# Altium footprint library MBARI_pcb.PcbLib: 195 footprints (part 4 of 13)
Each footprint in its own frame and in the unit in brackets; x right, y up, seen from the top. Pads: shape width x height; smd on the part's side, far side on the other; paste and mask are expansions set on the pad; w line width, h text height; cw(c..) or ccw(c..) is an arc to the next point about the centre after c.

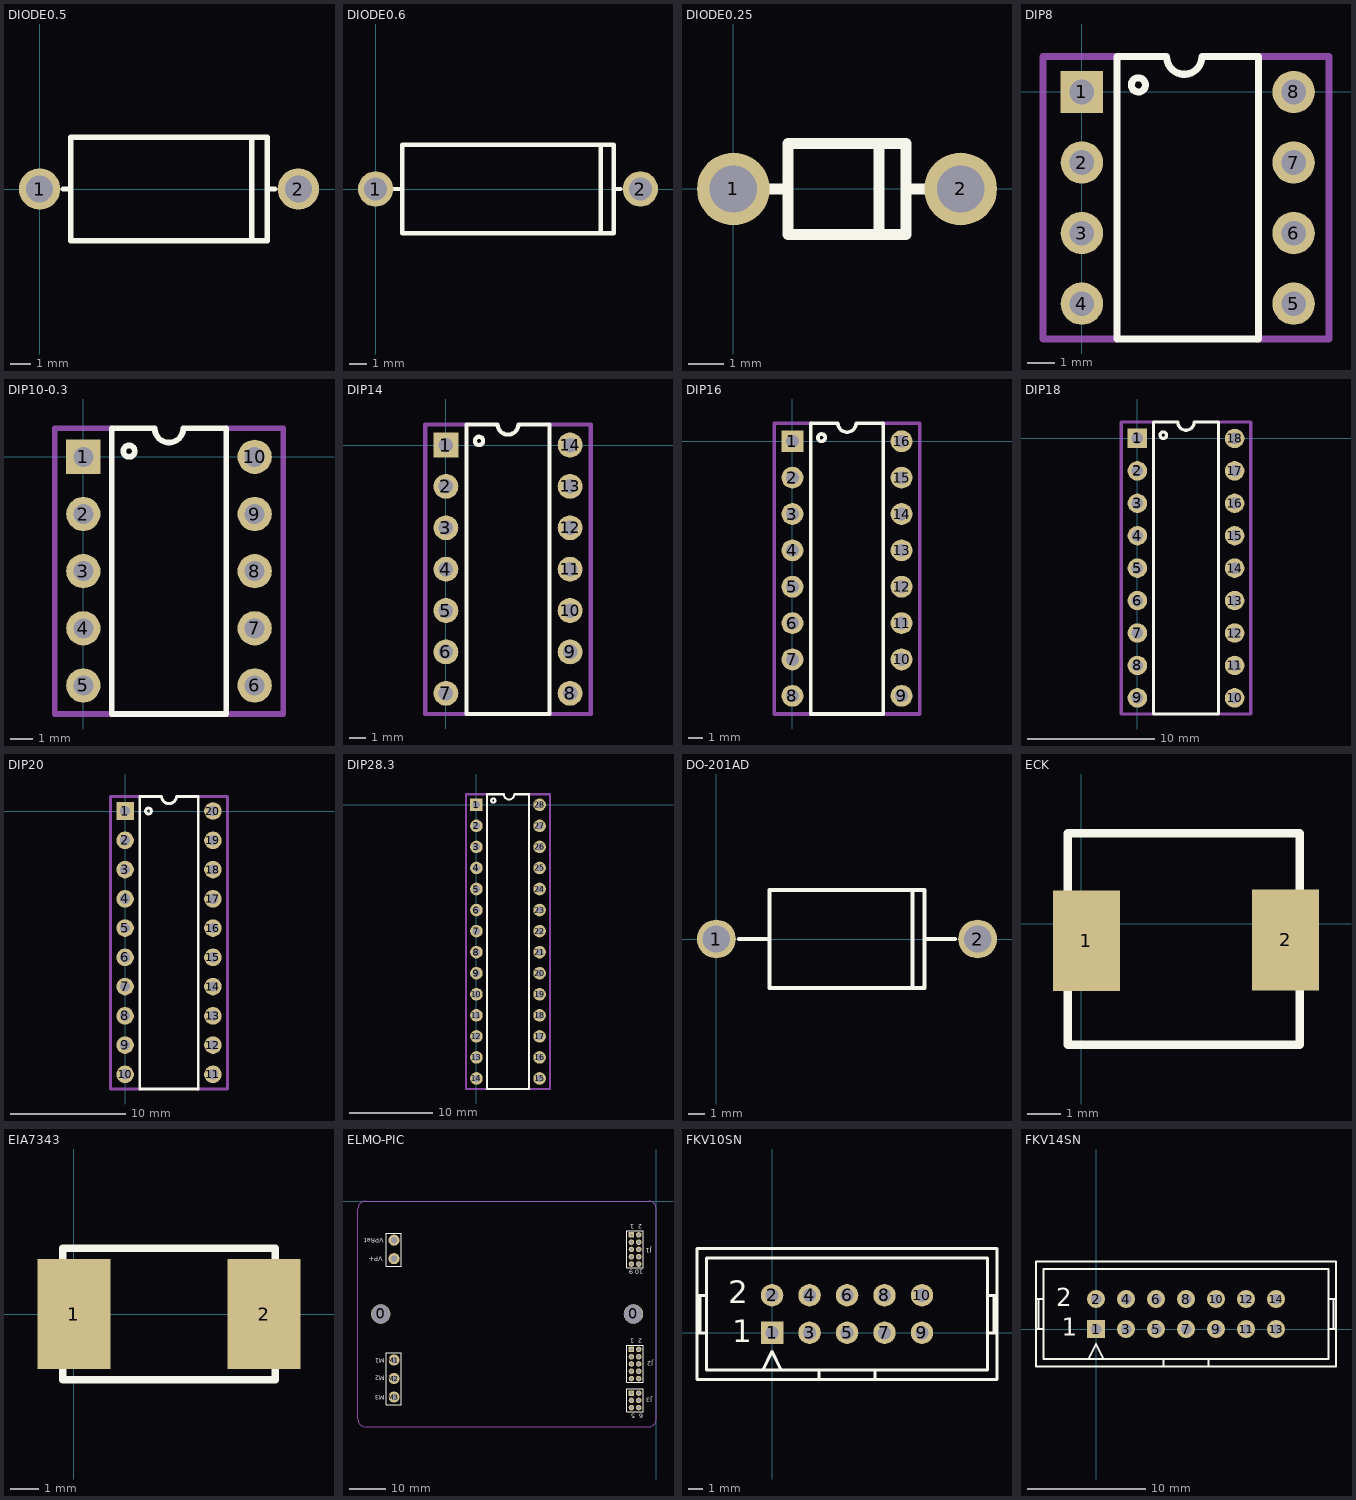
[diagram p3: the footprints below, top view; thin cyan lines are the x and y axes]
## DIODE0.5 [mil]
pads (2):
  round 80 hole 52: 1(0,0) 2(500,0)
TopOverlay:
  lines w10: 45,0 60,0 ; 410,-100 410,100 ; 440,0 455,0 ; 60,0 60,-100 440,-100 440,100 60,100 60,0

## DIODE0.6 [mil]
pads (2):
  round 80 hole 52: 1(0,0) 2(600,0)
TopOverlay:
  lines w10: 40,0 55,0 ; 510,-100 510,100 ; 540,0 555,0 ; 60,-100 540,-100 540,100 60,100 60,0 60,-100

## DIODE0.25 [mil]
pads (2):
  round 80 hole 52: 1(0,0) 2(250,0)
TopOverlay:
  lines w12: 40,0 60,0 ; 160,-50 160,50 ; 190,0 210,0 ; 60,-50 190,-50 190,50 60,50 60,-50

## DIP8 [mil]
pads (8):
  rect 60x60 hole 35: 1(0,0)
  round 60 hole 35: 2(0,-100) 3(0,-200) 4(0,-300) 5(300,-300) 6(300,-200) 7(300,-100) 8(300,0)
TopOverlay:
  circle w10: c80,10 r10
  lines w10: 50,-350 50,50 120,50 ccw(c145,50) 170,50 250,50 250,-350 50,-350
Mechanical1:
  lines w10: 50,-350 -55,-350 -55,50 50,50 ; 249,-350 350,-350 350,50 249,50

## DIP10-0.3 [mil] "10 pin DIP 0.3\" spacing"
pads (10):
  rect 60x60 hole 35: 1(0,0)
  round 60 hole 35: 2(0,-100) 3(0,-200) 4(0,-300) 5(0,-400) 6(300,-400) 7(300,-300) 8(300,-200) 9(300,-100) 10(300,0)
TopOverlay:
  circle w10: c80,10 r10
  lines w10: 50,-450 50,50 125,50 ccw(c150,50) 175,50 250,50 250,-450 50,-450
Mechanical1:
  lines w10: 50,-450 -50,-450 -50,50 50,50 ; 250,-450 350,-450 350,50 250,50

## DIP14 [mil]
pads (14):
  rect 60x60 hole 35: 1(0,0)
  round 60 hole 35: 2(0,-100) 3(0,-200) 4(0,-300) 5(0,-400) 6(0,-500) 7(0,-600) 8(300,-600) 9(300,-500) 10(300,-400) 11(300,-300) 12(300,-200) 13(300,-100) 14(300,0)
TopOverlay:
  circle w10: c80,10 r10
  lines w10: 50,-650 250,-650 250,50 175,50 cw(c150,50) 125,50 50,50 50,-650
Mechanical1:
  lines w10: 50,-650 -50,-650 -50,50 50,50 ; 250,-650 350,-650 350,50 250,50

## DIP16 [mil]
pads (16):
  rect 60x60 hole 35: 1(0,0)
  round 60 hole 35: 2(0,-100) 3(0,-200) 4(0,-300) 5(0,-400) 6(0,-500) 7(0,-600) 8(0,-700) 9(300,-700) 10(300,-600) 11(300,-500) 12(300,-400) 13(300,-300) 14(300,-200) 15(300,-100) 16(300,0)
TopOverlay:
  circle w10: c80,10 r10
  lines w10: 50,-750 250,-750 250,50 175,50 cw(c150,50) 125,50 50,50 50,-750
Mechanical1:
  lines w10: 50,-750 -50,-750 -50,50 50,50 ; 250,-750 350,-750 350,50 250,50

## DIP18 [mil]
pads (18):
  rect 60x60 hole 35: 1(0,0)
  round 60 hole 35: 2(0,-100) 3(0,-200) 4(0,-300) 5(0,-400) 6(0,-500) 7(0,-600) 8(0,-700) 9(0,-800) 10(300,-800) 11(300,-700) 12(300,-600) 13(300,-500) 14(300,-400) 15(300,-300) 16(300,-200) 17(300,-100) 18(300,0)
TopOverlay:
  circle w10: c80,10 r10
  lines w10: 175,50.27 cw(c150,50.27) 125,50.27 50,50.27 50,-849.73 249.45,-849.73 ; 175,50.27 250,50.27 250,-849.17
Mechanical1:
  lines w10: 49.73,-849.73 -50,-849.73 -50,50.27 50,50.27 ; 250,50.27 350,50.27 350,-849.73 250.28,-849.73

## DIP20 [mil]
pads (20):
  rect 60x60 hole 35: 1(0,0)
  round 60 hole 35: 2(0,-100) 3(0,-200) 4(0,-300) 5(0,-400) 6(0,-500) 7(0,-600) 8(0,-700) 9(0,-800) 10(0,-900) 11(300,-900) 12(300,-800) 13(300,-700) 14(300,-600) 15(300,-500) 16(300,-400) 17(300,-300) 18(300,-200) 19(300,-100) 20(300,0)
TopOverlay:
  circle w10: c80,0 r10
  lines w10: 50,50 50,-950 250,-950 250,50 175,50.27 ; 50,50.27 125,50.27 ccw(c150,50.27) 175,50.27
Mechanical1:
  lines w10: 50,-950 -50,-950 -50,50 50,50 ; 250,-950 350,-950 350,50 250,50

## DIP28.3 [mil]
pads (28):
  rect 60x60 hole 35: 1(0,0)
  round 60 hole 35: 2(0,-100) 3(0,-200) 4(0,-300) 5(0,-400) 6(0,-500) 7(0,-600) 8(0,-700) 9(0,-800) 10(0,-900) 11(0,-1000) 12(0,-1100) 13(0,-1200) 14(0,-1300) 15(300,-1300) 16(300,-1200) 17(300,-1100) 18(300,-1000) 19(300,-900) 20(300,-800) 21(300,-700) 22(300,-600) 23(300,-500) 24(300,-400) 25(300,-300) 26(300,-200) 27(300,-100) 28(300,0)
TopOverlay:
  circle w10: c80,20 r10
  lines w10: 50,-1350 250,-1350 250,50 180,50 cw(c155,50) 130,50 50,50 50,-1350
Mechanical1:
  lines w10: 50,-1350 -50,-1350 -50,50 50,50 ; 250,-1350 350,-1350 350,50 250,50

## DO-201AD [mil]
pads (2):
  round 95 hole 67: 1(0,0) 2(640,0)
TopOverlay:
  lines w10: 55,0 130,0 ; 480,-120 480,120 ; 510,0 585,0 ; 130,0 130,120 510,120 510,-120 130,-120 130,0

## ECK [mm]
pads (2):
  rect 2x3 smd: 1(0.15,-0.5) 2(6.075,-0.475)
TopOverlay:
  lines w0.254: -0.4,-2 -0.4,-3.6 3.1,-3.6 6.5,-3.6 6.5,-1.975 ; -0.4,1 -0.4,2.7 3.1,2.7 6.5,2.7 6.5,1

## EIA7343 [mil] "EIA 7343 size SMD"
height 120
pads (2):
  rect 100x150 smd: 1(0,0) 2(260,0)
TopOverlay:
  lines w10: -15,-75 -15,-90 275,-90 275,-75 ; -15,75 -15,90 275,90 275,75

## ELMO-PIC [mil]
pads (33):
  round 210 hole 201: 0(-2982.28,-1220.47) 0(-246.06,-1220.47)
  rect 60x60 hole 35: J1.1(-267.32,-364.17) J2.1(-267.32,-1604.33) J3.1(-267.32,-2076.77)
  round 60 hole 35: J1.2(-188.58,-364.17) J1.3(-267.32,-442.91) J1.4(-188.58,-442.91) J1.5(-267.32,-521.65) J1.6(-188.58,-521.65) J1.7(-267.32,-600.39) J1.8(-188.58,-600.39) J1.9(-267.32,-679.13) J1.10(-188.58,-679.13) J2.2(-188.58,-1604.33) J2.3(-267.32,-1683.07) J2.4(-188.58,-1683.07) J2.5(-267.32,-1761.81) J2.6(-188.58,-1761.81) J2.7(-267.32,-1840.55) J2.8(-188.58,-1840.55) J2.9(-267.32,-1919.29) J2.10(-188.58,-1919.29) J3.2(-188.58,-2076.77) J3.3(-267.32,-2155.51) J3.4(-188.58,-2155.51) J3.5(-267.32,-2234.25) J3.6(-188.58,-2234.25)
  round 120 hole 70: M1(-2838.58,-1719.29) M2(-2838.58,-1919.29) M3(-2838.58,-2119.29) VP+(-2838.58,-621.65) VPRet(-2838.58,-421.65)
TopOverlay:
  lines w10: -145.67,-2031.5 -318.9,-2031.5 -318.9,-2279.53 -141.73,-2279.53 -141.73,-2031.5 ; -145.67,-1559.06 -318.9,-1559.06 -318.9,-1960.63 -141.73,-1960.63 -141.73,-1559.06 ; -145.67,-318.9 -318.9,-318.9 -318.9,-720.47 -141.73,-720.47 -141.73,-318.9 ; -2921.26,-2200.79 -2921.26,-1641.73 -2759.84,-1641.73 -2759.84,-2200.79 -2921.26,-2200.79 ; -2921.26,-702.36 -2921.26,-344.09 -2759.84,-344.09 -2759.84,-702.36 -2921.26,-702.36
  text "M3" at -2940,-2100 h50
  text "M2" at -2940,-1890 h50
  text "M1" at -2940,-1700 h50
  text "VPRet" at -2950,-400 h50
  text "VP+" at -2960,-600 h50
  text "10 9" at -140,-740 h50
  text "6  5" at -140,-2300 h50
  text "2  1" at -150,-250 h50
  text "2  1" at -150,-1490 h50
  text "J1" at -50,-510 h50
  text "J2" at -30,-1730 h50
  text "J3" at -40,-2130 h50
Mechanical1:
  lines w10: -3228.35,-2362.2 ccw(c-3149.61,-2362.2) -3149.61,-2440.94 -78.74,-2440.94 ccw(c-78.74,-2362.2) 0,-2362.2 0,-78.74 ccw(c-78.74,-78.74) -78.74,0 -3149.61,0 ccw(c-3149.61,-78.74) -3228.35,-78.74 -3228.35,-2362.2

## FKV10SN [mil]
pads (10):
  rect 60x60 hole 35: 1(0,0)
  round 60 hole 35: 2(0,100) 3(100,0) 4(100,100) 5(200,0) 6(200,100) 7(300,0) 8(300,100) 9(400,0) 10(400,100)
TopOverlay:
  lines w8: -200,0 -175,0 ; -200,100 -175,100 ; -191.67,0 -191.67,100 ; -25,-100 0,-50 25,-100 ; 125,-125 125,-100 ; 275,-125 275,-100 ; 575,0 600,0 ; 575,100 600,100 ; 591.67,0 591.67,100 ; 125,-100 275,-100 ; 125,-100 -175,-100 -175,200 575,200 575,-100 275,-100 ; -200,-125 600,-125 600,225 -200,225 -200,-125
  text "1" at -106,-26 h60
  text "2" at -117,79 h60

## FKV14SN [mil]
pads (14):
  rect 60x60 hole 35: 1(0,0)
  round 60 hole 35: 2(0,100) 3(100,0) 4(100,100) 5(200,0) 6(200,100) 7(300,0) 8(300,100) 9(400,0) 10(400,100) 11(500,0) 12(500,100) 13(600,0) 14(600,100)
TopOverlay:
  lines w8: -200,0 -175,0 ; -200,100 -175,100 ; -191.67,0 -191.67,100 ; -25,-100 0,-50 25,-100 ; 225,-125 225,-100 ; 375,-125 375,-100 ; 775,0 800,0 ; 775,100 800,100 ; 791.67,0 791.67,100 ; 225,-100 375,-100 ; 225,-100 -175,-100 -175,200 775,200 775,-100 375,-100 ; -200,-125 800,-125 800,225 -200,225 -200,-125
  text "2" at -132,76 h60
  text "1" at -115,-23 h60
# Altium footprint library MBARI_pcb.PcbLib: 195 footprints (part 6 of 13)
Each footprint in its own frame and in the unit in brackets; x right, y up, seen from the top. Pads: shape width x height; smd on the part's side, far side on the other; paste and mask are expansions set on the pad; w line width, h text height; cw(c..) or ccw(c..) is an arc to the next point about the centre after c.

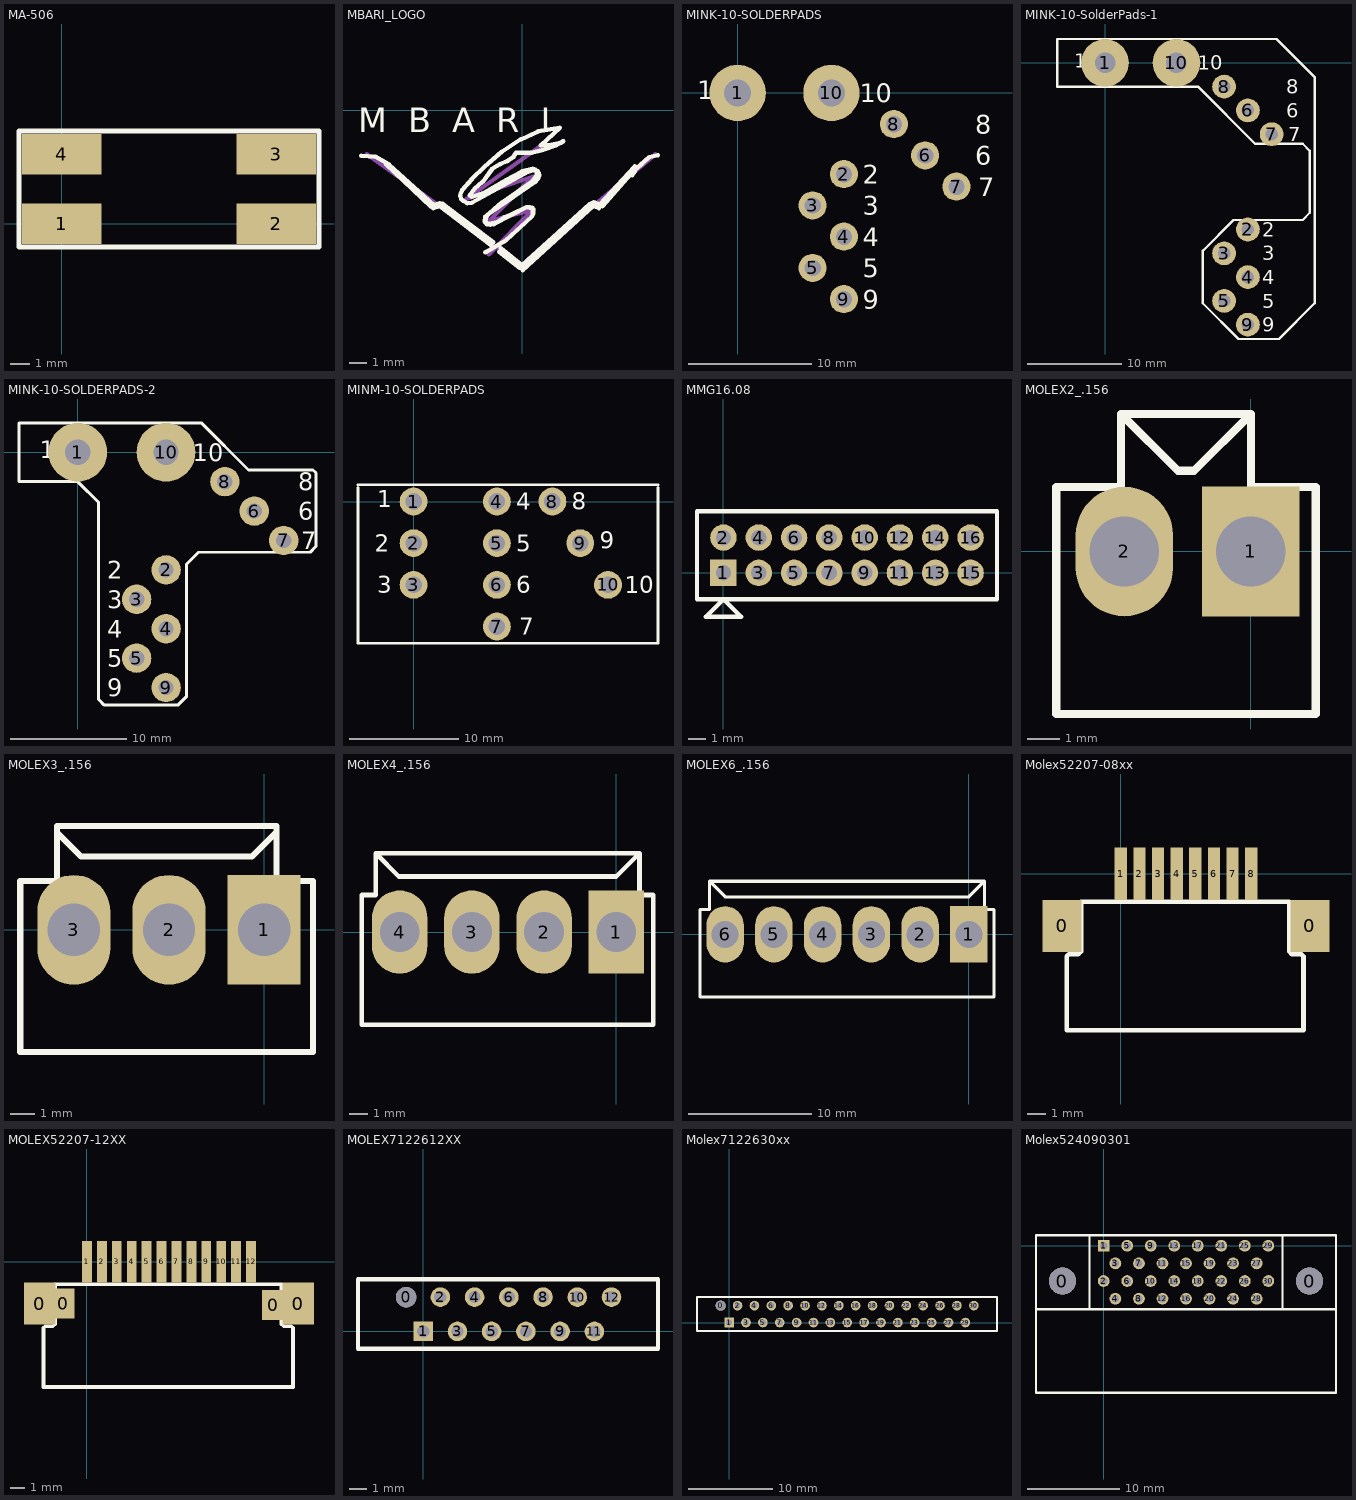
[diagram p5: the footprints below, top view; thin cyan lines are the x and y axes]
## MA-506 [mm] "Epson Quartz Crystal"
height 4.572
pads (4):
  rect 4.1x2.1 smd: 1(0,0) 2(11.1,0) 3(11.1,3.6) 4(0,3.6)
TopOverlay:
  lines w0.254: -2.2,-1.2 -2.2,4.8 13.3,4.8 13.3,-1.2 -2.2,-1.2

## MBARI_LOGO [mil]
TopOverlay:
  lines w10: -363,-103 -331,-105 -300,-123 -199,-214 -186,-210 -179,-211 -65,-298 ; -308,-121 -205,-218 ; -200,-221 -185,-217 -70,-305 ; -83,-321 -37,-294 22,-240 25,-233 25,-223 23,-220 17,-219 10,-219 ; -52,-319 -5,-356 ; -48,-312 0,-350 152,-212 161,-208 175,-213 254,-127 257,-132 286,-106 306,-102 ; 24,-234 24,-226 22,-222 17,-220 10,-219 ; 158,-216 173,-221 ; 180,-217 245,-144 ; 248,-147 254,-138 ; 10,-219 3,-222 -40,-242 -57,-253 -80,-257 -84,-252 -83,-240 -45,-208 23,-161 34,-145 30,-134 24,-132 0,-138 -36,-158 -84,-186 -114,-196 -118,-192 -107,-177 -89,-162 -67,-132 -49,-122 -34,-115 -21,-107 -14,-96 21,-96 44,-91 60,-85 76,-80 93,-70 88,-74 59,-79 42,-79 85,-40 36,-48 -3,-66 -46,-94 -85,-128 -113,-155 -135,-180 -139,-188 -140,-194 -137,-201 -132,-205 -124,-210 -114,-209 14,-139 24,-136 31,-136 35,-138 37,-142 39,-147 36,-154 28,-163 -67,-228 -78,-236 -82,-244 -83,-250 -79,-257 -72,-259 -64,-257 10,-219 ; 1,-361 160,-216 1,-361
  text "M  B  A  R  I" at -370,-50 h55
Mechanical3:
  lines w10: -350,-100 0,-350 300,-100 ; -75,-325 25,-225 -75,-250 25,-150 -125,-200 50,-75

## MINK-10-SOLDERPADS [mil]
pads (10):
  round 180 hole 86: 1(0,0) 10(300,0)
  round 90 hole 52: 2(340,-260) 3(240,-360) 4(340,-460) 5(240,-560) 6(600,-200) 7(700,-300) 8(500,-100) 9(340,-660)
TopOverlay:
  text "9" at 400,-690 h60
  text "8" at 760,-130 h60
  text "7" at 770,-330 h60
  text "6" at 760,-230 h60
  text "5" at 400,-590 h60
  text "4" at 400,-490 h60
  text "10" at 390,-30 h60
  text "3" at 400,-390 h60
  text "2" at 400,-290 h60
  text "1" at -130,-20 h60

## MINK-10-SolderPads-1 [mil]
pads (10):
  round 200 hole 86: 1(0,0) 10(300,0)
  round 100 hole 52: 2(600,-700) 3(500,-800) 4(600,-900) 5(500,-1000) 6(600,-200) 7(700,-300) 8(500,-100) 9(600,-1100)
TopOverlay:
  lines w10: -200,-100 390,-100 630,-340 830,-340 860,-370 860,-630 830,-660 540,-660 410,-790 410,-1010 560,-1160 730,-1160 880,-1010 880,-60 720,100 -200,100 -200,-100
  text "1" at -130,-20 h60
  text "2" at 660,-730 h60
  text "3" at 660,-830 h60
  text "10" at 390,-30 h60
  text "4" at 660,-930 h60
  text "5" at 660,-1030 h60
  text "6" at 760,-230 h60
  text "7" at 770,-330 h60
  text "8" at 760,-130 h60
  text "9" at 660,-1130 h60

## MINK-10-SOLDERPADS-2 [mil]
pads (10):
  round 200 hole 86: 1(0,0) 10(300,0)
  round 100 hole 52: 2(300,-400) 3(200,-500) 4(300,-600) 5(200,-700) 6(600,-200) 7(700,-300) 8(500,-100) 9(300,-800)
TopOverlay:
  lines w10: -200,-100 0,-100 70,-170 70,-840 90,-860 340,-860 370,-830 370,-380 410,-340 790,-340 810,-320 810,-70 800,-60 580,-60 420,100 -200,100 -200,-100
  text "9" at 100,-830 h60
  text "8" at 750,-130 h60
  text "7" at 760,-330 h60
  text "6" at 750,-230 h60
  text "5" at 100,-730 h60
  text "4" at 100,-630 h60
  text "10" at 390,-30 h60
  text "3" at 100,-530 h60
  text "2" at 100,-430 h60
  text "1" at -130,-20 h60

## MINM-10-SOLDERPADS [mil] "MIN-M 10/16AWG holes"
pads (10):
  round 100 hole 59.5: 1(0,0) 2(0,-150) 3(0,-300) 4(300,0) 5(300,-150) 6(300,-300) 7(300,-450) 8(500,0) 9(600,-150) 10(700,-300)
TopOverlay:
  lines w10: -200,50 -200,-510 880,-510 880,50 ; -200,60 880,60
  text "1" at -130,-20 h60
  text "2" at -140,-180 h60
  text "3" at -130,-330 h60
  text "10" at 760,-330 h60
  text "4" at 370,-30 h60
  text "5" at 370,-180 h60
  text "6" at 370,-330 h60
  text "7" at 380,-480 h60
  text "8" at 570,-30 h60
  text "9" at 670,-170 h60

## MMG16.08 [mil]
pads (16):
  rect 60x60 hole 35: 1(0,0)
  round 60 hole 35: 2(0,80) 3(80,0) 4(80,80) 5(160,0) 6(160,80) 7(240,0) 8(240,80) 9(320,0) 10(320,80) 11(400,0) 12(400,80) 13(480,0) 14(480,80) 15(560,0) 16(560,80)
TopOverlay:
  lines w10: -60,-60 -60,140 620,140 620,-60 -60,-60 ; -40,-100 0,-60 40,-100 -40,-100

## MOLEX2_.156 [mil]
pads (2):
  rect 120x160 hole 86: 1(0,0)
  oval 120x160 hole 86: 2(-156,0)
TopOverlay:
  lines w10: -160,169.57 -90,99.57 -70,99.57 0,169.57 ; -160,169.57 -160,79.57 -240,79.57 -240,-200.43 80,-200.43 80,79.57 0,79.57 0,169.57 ; -160,169.57 0,169.57

## MOLEX3_.156 [mil]
pads (3):
  rect 120x180 hole 86: 1(0,0)
  oval 120x180 hole 86: 2(-156,0) 3(-312,0)
TopOverlay:
  lines w10: -340,170 20,170 ; -340,170 -340,80 -400,80 -400,-200 80,-200 80,80 20,80 20,170 ; -340,170 -340,160 -300,120 -20,120 20,160 20,170

## MOLEX4_.156 [mil]
pads (4):
  rect 120x180 hole 86: 1(0,0)
  oval 120x180 hole 86: 2(-156,0) 3(-312,0) 4(-468,0)
TopOverlay:
  lines w10: -520,170 50,170 ; -520,170 -520,80 -550,80 -550,-200 80,-200 80,80 50,80 50,170 ; -520,170 -470,120 0,120 40,160 50,170

## MOLEX6_.156 [mil]
pads (6):
  rect 120x180 hole 86: 1(0,0)
  oval 120x180 hole 86: 2(-156,0) 3(-312,0) 4(-468,0) 5(-624,0) 6(-780,0)
TopOverlay:
  lines w10: -830,170 50,170 ; -830,170 -830,80 -860,80 -860,-200 80,-200 80,80 50,80 50,170 ; -830,170 -820,160 -780,120 0,120 40,160 50,170

## Molex52207-08xx [mm]
pads (10):
  rect 2.1x2.8 smd: 0(-3.15,-2.8) 0(10.15,-2.8)
  rect 0.66x2.8 smd: 1(0,0) 2(1,0) 3(2,0) 4(3,0) 5(4,0) 6(5,0) 7(6,0) 8(7,0)
TopOverlay:
  lines w0.254: -2.9,-8.4 -2.9,-4.424 -2.794,-4.318 -2.286,-4.318 -2.138,-4.17 -2.138,-1.5 9.038,-1.5 9.038,-4.17 9.186,-4.318 9.694,-4.318 9.8,-4.424 9.8,-8.4 -2.9,-8.4

## MOLEX52207-12XX [mm]
pads (16):
  rect 2.1x2.8 smd: 0(-3.15,-2.8) 0(14.15,-2.8)
  rect 1.524x2.032 smd: 0(-1.6,-2.8) 0(12.5,-2.9)
  rect 0.66x2.8 smd: 1(0,0) 2(1,0) 3(2,0) 4(3,0) 5(4,0) 6(5,0) 7(6,0) 8(7,0) 9(8,0) 10(9,0) 11(10,0) 12(11,0)
TopOverlay:
  lines w0.254: -2.9,-8.4 13.8,-8.4 13.8,-4.424 13.694,-4.318 13.186,-4.318 13.038,-4.17 13.038,-1.5 -2.138,-1.5 -2.138,-4.17 -2.286,-4.318 -2.794,-4.318 -2.9,-4.424 -2.9,-8.4

## MOLEX7122612XX [mil]
pads (13):
  round 47 hole 47: 0(-39.37,78.74)
  rect 45x45 hole 28: 1(0,0)
  round 45 hole 28: 2(39.37,78.74) 3(78.74,0) 4(118.11,78.74) 5(157.48,0) 6(196.85,78.74) 7(236.22,0) 8(275.59,78.74) 9(314.96,0) 10(354.33,78.74) 11(393.7,0) 12(433.07,78.74)
TopOverlay:
  lines w10: -150,-40 540,-40 540,120 -150,120 -150,-40

## Molex7122630xx [mil]
pads (31):
  round 47 hole 47: 0(-39.37,78.74)
  rect 45x45 hole 28: 1(0,0)
  round 45 hole 28: 2(39.37,78.74) 3(78.74,0) 4(118.11,78.74) 5(157.48,0) 6(196.85,78.74) 7(236.22,0) 8(275.59,78.74) 9(314.96,0) 10(354.33,78.74) 11(393.7,0) 12(433.07,78.74) 13(472.44,0) 14(511.81,78.74) 15(551.18,0) 16(590.55,78.74) 17(629.92,0) 18(669.29,78.74) 19(708.66,0) 20(748.03,78.74) 21(787.4,0) 22(826.77,78.74) 23(866.14,0) 24(905.51,78.74) 25(944.88,0) 26(984.25,78.74) 27(1023.62,0) 28(1062.99,78.74) 29(1102.36,0) 30(1141.73,78.74)
TopOverlay:
  lines w10: -150,-40 1250,-40 1250,120 -150,120 -150,-40

## Molex524090301 [mil]
pads (32):
  round 115 hole 115: 0(-175,-150) 0(875,-150)
  rect 50x50 hole 32: 1(0,0)
  round 50 hole 32: 2(0,-150) 3(50,-75) 4(50,-225) 5(100,0) 6(100,-150) 7(150,-75) 8(150,-225) 9(200,0) 10(200,-150) 11(250,-75) 12(250,-225) 13(300,0) 14(300,-150) 15(350,-75) 16(350,-225) 17(400,0) 18(400,-150) 19(450,-75) 20(450,-225) 21(500,0) 22(500,-150) 23(550,-75) 24(550,-225) 25(600,0) 26(600,-150) 27(650,-75) 28(650,-225) 29(700,0) 30(700,-150)
TopOverlay:
  lines w10: -287.5,-270 987.5,-270 ; -60,-270 -60,45 ; 760,-270 760,45 ; -287.5,-625 987.5,-625 987.5,45 -287.5,45 -287.5,-625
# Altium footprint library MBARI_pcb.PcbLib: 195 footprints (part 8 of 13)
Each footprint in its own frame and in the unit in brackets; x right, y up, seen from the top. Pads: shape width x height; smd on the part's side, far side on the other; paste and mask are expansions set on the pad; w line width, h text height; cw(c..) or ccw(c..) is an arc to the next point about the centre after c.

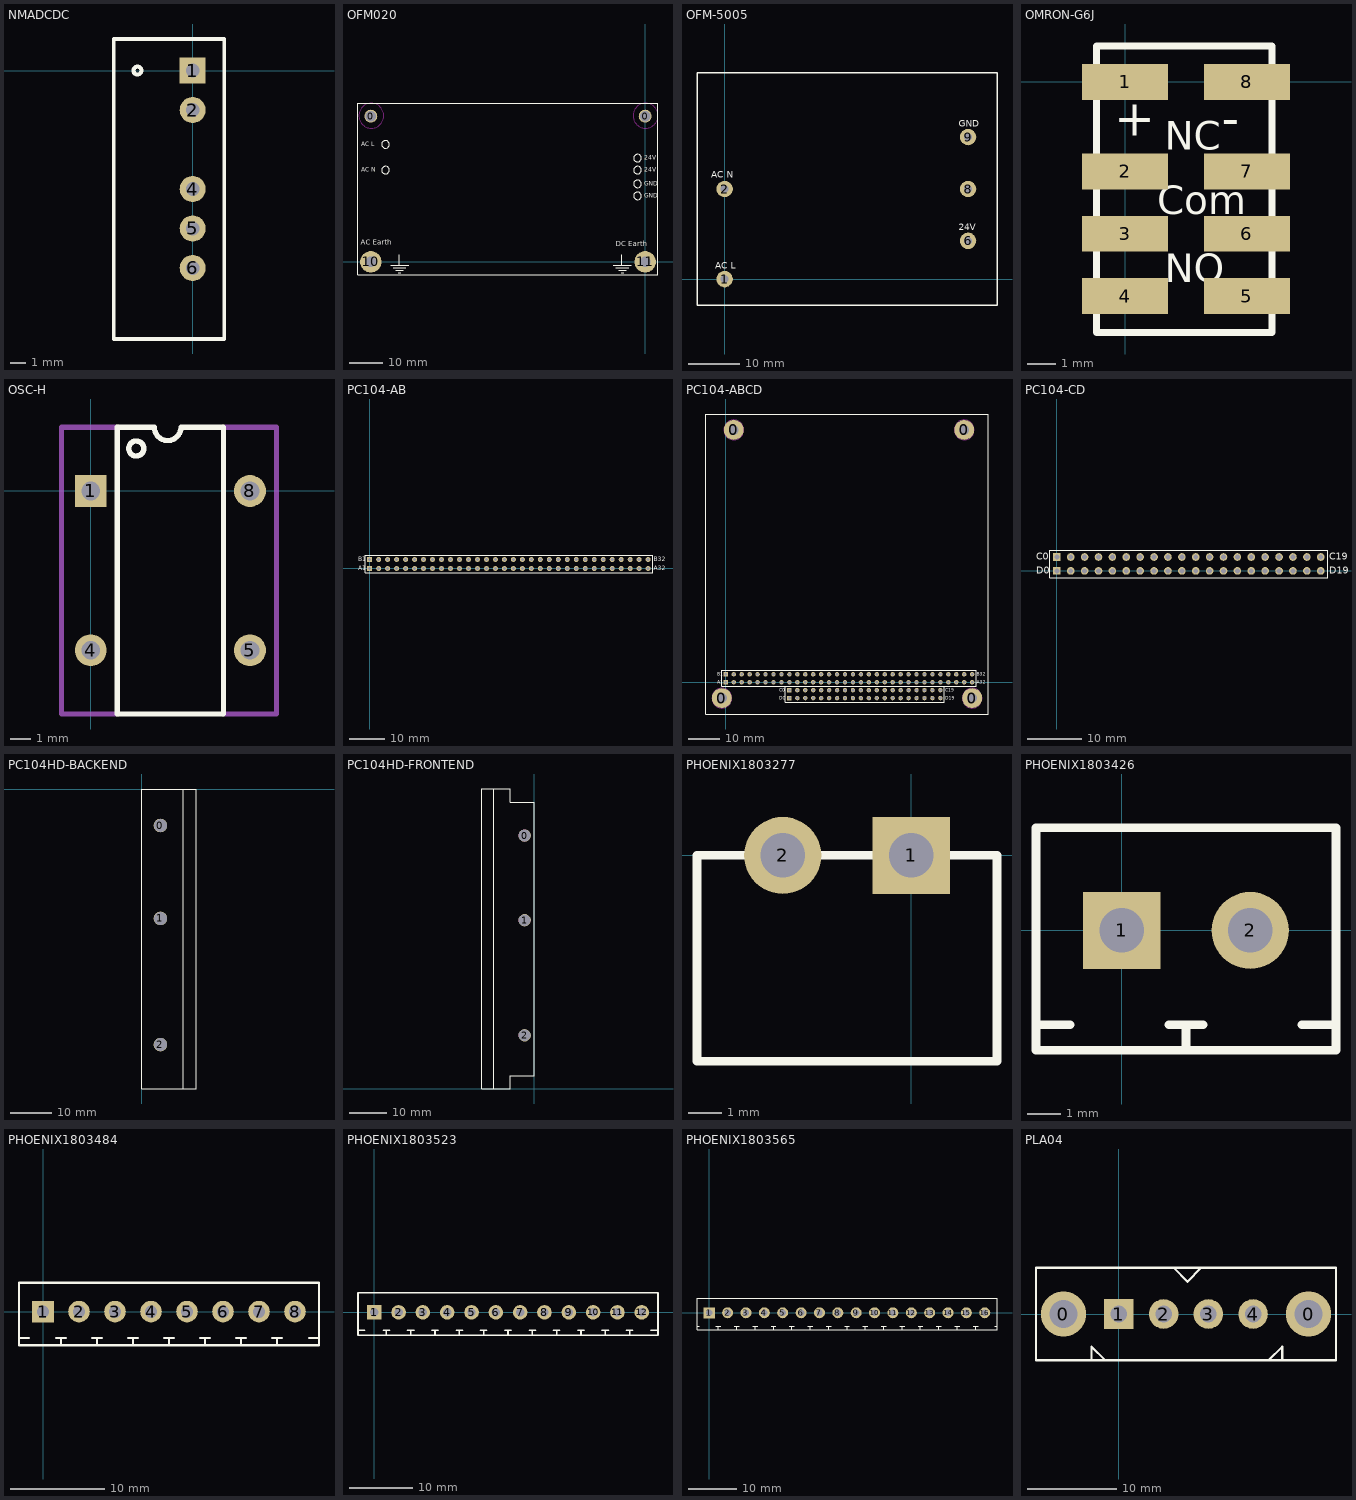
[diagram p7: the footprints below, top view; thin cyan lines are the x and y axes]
## NMADCDC [mil]
pads (5):
  rect 66x66 hole 35: 1(0,0)
  round 66 hole 35: 2(0,-100) 4(0,-300) 5(0,-400) 6(0,-500)
TopOverlay:
  circle w10: c-140,0 r10
  lines w10: -200,-680 -200,80 0,80 80,80 80,-680 -200,-680

## OFM020 [mil]
pads (4):
  round 150 hole 125: 0(-3200,1700) 0(0,1700)
  round 250 hole 125: 10(-3200,0) 11(0,0)
TopOverlay:
  circle w10: c-90,770 r44.72
  circle w10: c-90,1070 r44.72
  circle w10: c-90,910 r44.72
  circle w10: c-90,1210 r44.72
  circle w10: c-3030,1070 r44.72
  circle w10: c-3030,1370 r44.72
  lines w10: -2970,-40 -2760,-40 ; -2940,-70 -2790,-70 ; -2910,-100 -2820,-100 ; -2880,-130 -2850,-130 ; -2870,-40 -2870,80 ; -370,-40 -160,-40 ; -340,-70 -190,-70 ; -310,-100 -220,-100 ; -280,-130 -250,-130 ; -270,-40 -270,80 ; -3350,-150 150,-150 150,1850 -3350,1850 -3350,-150
  text "GND" at -10,750 h50
  text "24V" at -10,1050 h50
  text "24V" at -10,1190 h50
  text "AC N" at -3310,1050 h50
  text "AC L" at -3310,1350 h50
  text "GND" at -10,890 h50
  text "AC Earth" at -3320,200 h60
  text "DC Earth" at -340,180 h60
KeepOutLayer:
  circle w10: c-3195,1705 r145
  circle w10: c5,1705 r145

## OFM-5005 [mil]
pads (5):
  round 125 hole 59.5: 1(0,0) 2(0,685) 6(1850,291) 8(1850,685) 9(1850,1080)
TopOverlay:
  lines w10: -210,-200 -210,0 -210,1570 2070,1570 2070,-200 -210,-200
  text "AC L" at -70,80 h50
  text "24V" at 1780,370 h50
  text "AC N" at -100,770 h50
  text "GND" at 1780,1160 h50

## OMRON-G6J [mil]
pads (8):
  rect 120x50 smd: 1(0,0) 2(0,-125) 3(0,-212) 4(0,-299) 5(170,-299) 6(170,-212) 7(170,-125) 8(170,0)
TopOverlay:
  lines w10: -40,-350 -40,50 205,50 205,-350 -40,-350
  text "Com" at 45,-185 h40
  text "NO" at 55,-280 h40
  text "NC" at 55,-95 h40
  text "-" at 135,-75 h50
  text "+" at -15,-75 h50

## OSC-H [mil]
pads (4):
  rect 60x60 hole 35: 1(0,0)
  round 60 hole 35: 4(0,-300) 5(300,-300) 8(300,0)
TopOverlay:
  circle w10: c85.86,80 r14.14
  lines w10: 50,-420 50,120 120,120 ccw(c145,120) 170,120 250,120 250,-420 50,-420
Mechanical1:
  lines w10: 50,-420 -55,-420 -55,120 51,120 ; 250,-420 350,-420 350,120 250,120

## PC104-AB [mil] "PC/104 A&B rails"
height 440
pads (64):
  rect 55x55 hole 35: A1(0,0) B1(0,100)
  round 55 hole 35: A2(100,0) A3(200,0) A4(300,0) A5(400,0) A6(500,0) A7(600,0) A8(700,0) A9(800,0) A10(900,0) A11(1000,0) A12(1100,0) A13(1200,0) A14(1300,0) A15(1400,0) A16(1500,0) A17(1600,0) A18(1700,0) A19(1800,0) A20(1900,0) A21(2000,0) A22(2100,0) A23(2200,0) A24(2300,0) A25(2400,0) A26(2500,0) A27(2600,0) A28(2700,0) A29(2800,0) A30(2900,0) A31(3000,0) A32(3100,0) B2(100,100) B3(200,100) B4(300,100) B5(400,100) B6(500,100) B7(600,100) B8(700,100) B9(800,100) B10(900,100) B11(1000,100) B12(1100,100) B13(1200,100) B14(1300,100) B15(1400,100) B16(1500,100) B17(1600,100) B18(1700,100) B19(1800,100) B20(1900,100) B21(2000,100) B22(2100,100) B23(2200,100) B24(2300,100) B25(2400,100) B26(2500,100) B27(2600,100) B28(2700,100) B29(2800,100) B30(2900,100) B31(3000,100) B32(3100,100)
TopOverlay:
  lines w8: 3150,-50.39 3150,149.61 ; 3150,-50 -50,-50.39 -50,149.61 3150,150
  text "B1" at -130,80 h50
  text "A1" at -130,-20 h50
  text "A32" at 3160,-20.39 h50
  text "B32" at 3160,79.61 h50

## PC104-ABCD [mil] "PC104 Outline and ABCD Rails"
height 600
pads (108):
  round 250 hole 125: 0(-50,-200) 0(100,3175) 0(3000,3175) 0(3100,-200)
  rect 55x55 hole 35: A1(0,0) B1(0,100) C0(800,-100) D0(800,-200)
  round 55 hole 35: A2(100,0) A3(200,0) A4(300,0) A5(400,0) A6(500,0) A7(600,0) A8(700,0) A9(800,0) A10(900,0) A11(1000,0) A12(1100,0) A13(1200,0) A14(1300,0) A15(1400,0) A16(1500,0) A17(1600,0) A18(1700,0) A19(1800,0) A20(1900,0) A21(2000,0) A22(2100,0) A23(2200,0) A24(2300,0) A25(2400,0) A26(2500,0) A27(2600,0) A28(2700,0) A29(2800,0) A30(2900,0) A31(3000,0) A32(3100,0) B2(100,100) B3(200,100) B4(300,100) B5(400,100) B6(500,100) B7(600,100) B8(700,100) B9(800,100) B10(900,100) B11(1000,100) B12(1100,100) B13(1200,100) B14(1300,100) B15(1400,100) B16(1500,100) B17(1600,100) B18(1700,100) B19(1800,100) B20(1900,100) B21(2000,100) B22(2100,100) B23(2200,100) B24(2300,100) B25(2400,100) B26(2500,100) B27(2600,100) B28(2700,100) B29(2800,100) B30(2900,100) B31(3000,100) B32(3100,100) C1(900,-100) C2(1000,-100) C3(1100,-100) C4(1200,-100) C5(1300,-100) C6(1400,-100) C7(1500,-100) C8(1600,-100) C9(1700,-100) C10(1800,-100) C11(1900,-100) C12(2000,-100) C13(2100,-100) C14(2200,-100) C15(2300,-100) C16(2400,-100) C17(2500,-100) C18(2600,-100) C19(2700,-100) D1(900,-200) D2(1000,-200) D3(1100,-200) D4(1200,-200) D5(1300,-200) D6(1400,-200) D7(1500,-200) D8(1600,-200) D9(1700,-200) D10(1800,-200) D11(1900,-200) D12(2000,-200) D13(2100,-200) D14(2200,-200) D15(2300,-200) D16(2400,-200) D17(2500,-200) D18(2600,-200) D19(2700,-200)
TopOverlay:
  lines w8: 3150,-50.39 3150,149.61 ; 3150,-50 -50,-50.39 -50,149.61 3150,150 ; 750,-250.39 2750,-250 2750,-50 750,-50.39 750,-250.39
  lines w10: -250,-400 3300,-400 3300,3375 -250,3375 -250,-400
  text "B1" at -110,80 h40
  text "A1" at -110,-20 h40
  text "A32" at 3160,-20.39 h40
  text "B32" at 3160,79.61 h40
  text "C19" at 2760,-120.39 h40
  text "D19" at 2760,-220.39 h40
  text "D0" at 670,-220 h40
  text "C0" at 670,-120 h40
KeepOutLayer:
  circle w10: c3100,-200 r125
  circle w10: c3000,3175 r125
  circle w10: c100,3175 r125
  circle w10: c-50,-200 r125

## PC104-CD [mil] "PC/104 C&D rails"
height 440
pads (40):
  rect 55x55 hole 35: C0(0,100) D0(0,0)
  round 55 hole 35: C1(100,100) C2(200,100) C3(300,100) C4(400,100) C5(500,100) C6(600,100) C7(700,100) C8(800,100) C9(900,100) C10(1000,100) C11(1100,100) C12(1200,100) C13(1300,100) C14(1400,100) C15(1500,100) C16(1600,100) C17(1700,100) C18(1800,100) C19(1900,100) D1(100,0) D2(200,0) D3(300,0) D4(400,0) D5(500,0) D6(600,0) D7(700,0) D8(800,0) D9(900,0) D10(1000,0) D11(1100,0) D12(1200,0) D13(1300,0) D14(1400,0) D15(1500,0) D16(1600,0) D17(1700,0) D18(1800,0) D19(1900,0)
TopOverlay:
  lines w8: -50,-50.39 -50,149.61 1950,150 1950,-50 -50,-50.39
  text "C0" at -150,80 h50
  text "D0" at -150,-20 h50
  text "D19" at 1960,-20.39 h50
  text "C19" at 1960,79.61 h50

## PC104HD-BACKEND [mil] "PC104 HardDrive Mount for Back End"
height 560
pads (3):
  round 130 hole 125: 0(180,-350) 1(180,-1240) 2(180,-2450)
TopOverlay:
  lines w10: 400,-2875 400,0 ; 0,-2875 525,-2875 525,0 0,0 0,-2875

## PC104HD-FRONTEND [mil] "PC104 HardDrive Mount Front End"
height 530
pads (3):
  round 130 hole 125: 0(-100,2665) 1(-100,1775) 2(-100,565)
TopOverlay:
  lines w10: -425,0 -425,3155 ; -550,0 -250,0 -250,140 0,140 0,3015 -250,3015 -250,3155 -550,3155 -550,0

## PHOENIX1803277 [mil]
pads (2):
  rect 90x90 hole 52: 1(0,0)
  round 90 hole 52: 2(-150,0)
TopOverlay:
  lines w10: -250,-240 -250,0 100,0 100,-240 -250,-240

## PHOENIX1803426 [mil]
pads (2):
  rect 90x90 hole 52: 1(0,0)
  round 90 hole 52: 2(150,0)
TopOverlay:
  lines w10: -100,-110 -60,-110 ; 55,-110 95,-110 ; 75,-140 75,-110 ; 210,-110 250,-110 ; -100,-140 250,-140 250,120 -100,120 -100,-140

## PHOENIX1803484 [mil]
pads (8):
  rect 90x90 hole 52: 1(0,0)
  round 90 hole 52: 2(150,0) 3(300,0) 4(450,0) 5(600,0) 6(750,0) 7(900,0) 8(1050,0)
TopOverlay:
  lines w10: -100,-110 -60,-110 ; 55,-110 95,-110 ; 75,-140 75,-110 ; 205,-110 245,-110 ; 225,-140 225,-110 ; 355,-110 395,-110 ; 375,-140 375,-110 ; 505,-110 545,-110 ; 525,-140 525,-110 ; 655,-110 695,-110 ; 675,-140 675,-110 ; 805,-110 845,-110 ; 825,-140 825,-110 ; 955,-110 995,-110 ; 975,-140 975,-110 ; 1110,-110 1150,-110 ; -100,-140 -100,120 1150,120 1150,-140 -100,-140

## PHOENIX1803523 [mil]
pads (12):
  rect 90x90 hole 52: 1(0,0)
  round 90 hole 52: 2(150,0) 3(300,0) 4(450,0) 5(600,0) 6(750,0) 7(900,0) 8(1050,0) 9(1200,0) 10(1350,0) 11(1500,0) 12(1650,0)
TopOverlay:
  lines w10: -100,-110 -60,-110 ; 55,-110 95,-110 ; 75,-140 75,-110 ; 205,-110 245,-110 ; 225,-140 225,-110 ; 355,-110 395,-110 ; 375,-140 375,-110 ; 505,-110 545,-110 ; 525,-140 525,-110 ; 655,-110 695,-110 ; 675,-140 675,-110 ; 805,-110 845,-110 ; 825,-140 825,-110 ; 955,-110 995,-110 ; 975,-140 975,-110 ; 1105,-110 1145,-110 ; 1125,-140 1125,-110 ; 1255,-110 1295,-110 ; 1275,-140 1275,-110 ; 1405,-110 1445,-110 ; 1425,-140 1425,-110 ; 1555,-110 1595,-110 ; 1575,-140 1575,-110 ; 1705,-110 1745,-110 ; -100,-140 -100,120 1750,120 1750,-140 -100,-140

## PHOENIX1803565 [mil]
pads (16):
  rect 90x90 hole 52: 1(0,0)
  round 90 hole 52: 2(150,0) 3(300,0) 4(450,0) 5(600,0) 6(750,0) 7(900,0) 8(1050,0) 9(1200,0) 10(1350,0) 11(1500,0) 12(1650,0) 13(1800,0) 14(1950,0) 15(2100,0) 16(2250,0)
TopOverlay:
  lines w10: -100,-110 -80,-110 ; 55,-110 95,-110 ; 75,-140 75,-110 ; 205,-110 245,-110 ; 225,-140 225,-110 ; 355,-110 395,-110 ; 375,-140 375,-110 ; 505,-110 545,-110 ; 525,-140 525,-110 ; 655,-110 695,-110 ; 675,-140 675,-110 ; 805,-110 845,-110 ; 825,-140 825,-110 ; 955,-110 995,-110 ; 975,-140 975,-110 ; 1105,-110 1145,-110 ; 1125,-140 1125,-110 ; 1255,-110 1295,-110 ; 1275,-140 1275,-110 ; 1405,-110 1445,-110 ; 1425,-140 1425,-110 ; 1555,-110 1595,-110 ; 1575,-140 1575,-110 ; 1705,-110 1745,-110 ; 1725,-140 1725,-110 ; 1855,-110 1895,-110 ; 1875,-140 1875,-110 ; 2005,-110 2045,-110 ; 2025,-140 2025,-110 ; 2155,-110 2195,-110 ; 2175,-140 2175,-110 ; 2330,-110 2350,-110 ; -100,-140 2350,-140 2350,120 -100,120 -100,-140

## PLA04 [mil] "Positronic 1x4 pin"
pads (6):
  round 200 hole 125: 0(-244.5,0) 0(835.5,0)
  rect 130x130 hole 73: 1(0,0)
  round 130 hole 73: 2(197,0) 3(394,0) 4(591,0)
TopOverlay:
  lines w10: -120.5,-204 -120.5,-144 -60.5,-204 ; 242,204 302.5,142.5 362,204 ; 659.5,-204 719.5,-144 719.5,-204 ; -365.5,-204 956.5,-204 956.5,204 -365.5,204 -365.5,-204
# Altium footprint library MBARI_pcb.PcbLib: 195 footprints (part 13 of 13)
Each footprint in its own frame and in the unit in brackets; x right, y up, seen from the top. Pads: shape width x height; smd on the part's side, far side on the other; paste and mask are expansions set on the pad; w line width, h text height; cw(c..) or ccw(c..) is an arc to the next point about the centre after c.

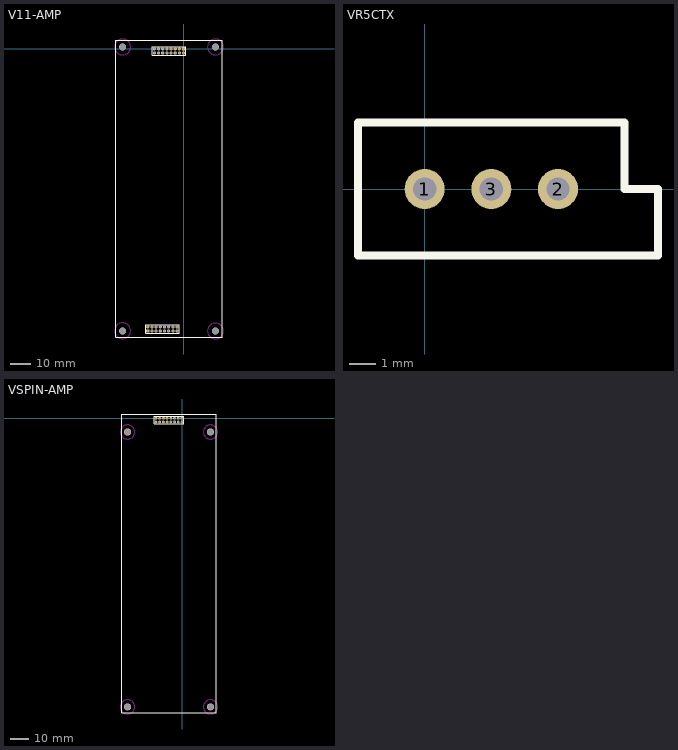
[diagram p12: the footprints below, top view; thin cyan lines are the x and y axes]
## V11-AMP [mil]
pads (36):
  round 130 hole 125: 0(-1150,-5320) 0(-1150,35) 0(600,-5320) 0(600,35)
  rect 60x60 hole 35: M1(-675,-5320) S1(0,0)
  round 60 hole 35: M2(-675,-5241.26) M3(-596.26,-5320) M4(-596.26,-5241.26) M5(-517.52,-5320) M6(-517.52,-5241.26) M7(-438.78,-5320) M8(-438.78,-5241.26) M9(-360.04,-5320) M10(-360.04,-5241.26) M11(-281.3,-5320) M12(-281.3,-5241.26) M13(-202.56,-5320) M14(-202.56,-5241.26) M15(-123.82,-5320) M16(-123.82,-5241.26) S2(0,-78.74) S3(-78.74,0) S4(-78.74,-78.74) S5(-157.48,0) S6(-157.48,-78.74) S7(-236.22,0) S8(-236.22,-78.74) S9(-314.96,0) S10(-314.96,-78.74) S11(-393.7,0) S12(-393.7,-78.74) S13(-472.44,0) S14(-472.44,-78.74) S15(-551.18,0) S16(-551.18,-78.74)
TopOverlay:
  lines w8: -715,-5360 -715,-5200 -85,-5200 -85,-5360 -715,-5360 ; -590,-120 -590,40 40,40 40,-120 -590,-120
  lines w10: -1275,-5440 -1275,160 725,160 725,-5440 -1275,-5440
BottomOverlay:
  text "Sense/Logic" at -120,-160 h45
  text "Phases" at -300,-5200 h45
KeepOutLayer:
  circle w10: c-1150,35 r150
  circle w10: c600,35 r150
  circle w10: c600,-5320 r150
  circle w10: c-1150,-5315 r150

## VR5CTX [mil]
pads (3):
  round 60 hole 35: 1(0,0) 2(200,0) 3(100,0)
TopOverlay:
  lines w12: -100,-100 350,-100 350,0 300,0 300,100 -100,100 -100,-100

## VSPIN-AMP [mil]
pads (20):
  round 150 hole 125: 0(-1150,-6090) 0(-1150,-290) 0(600,-6090) 0(600,-290)
  rect 60x60 hole 35: 1(0,0)
  round 60 hole 35: 2(0,-78.74) 3(-78.74,0) 4(-78.74,-78.74) 5(-157.48,0) 6(-157.48,-78.74) 7(-236.22,0) 8(-236.22,-78.74) 9(-314.96,0) 10(-314.96,-78.74) 11(-393.7,0) 12(-393.7,-78.74) 13(-472.44,0) 14(-472.44,-78.74) 15(-551.18,0) 16(-551.18,-78.74)
TopOverlay:
  lines w8: -590,-120 40,-120 40,40 -590,40 -590,-120
  lines w10: -1275,-6210 725,-6210 725,90 -1275,90 -1275,-6210
BottomOverlay:
  text "Amp Logic" at -140,-170 h45
KeepOutLayer:
  circle w10: c-1150,-290 r150
  circle w10: c600,-290 r150
  circle w10: c-1150,-6090 r150
  circle w10: c600,-6090 r150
